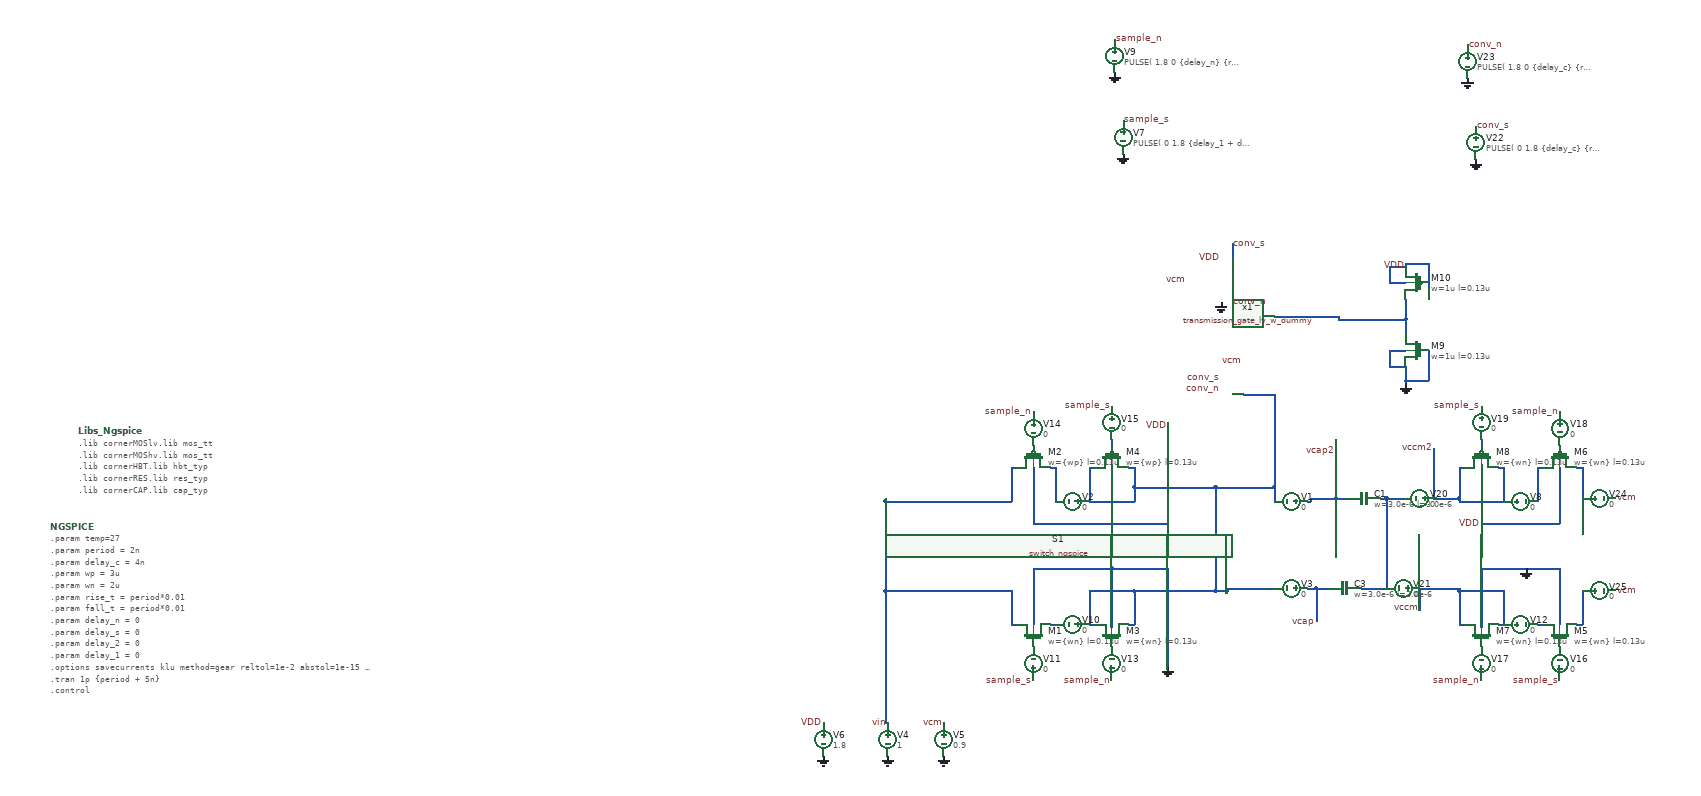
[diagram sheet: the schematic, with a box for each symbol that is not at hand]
v {xschem version=3.4.7 file_version=1.2}
G {}
K {}
V {}
S {}
E {}
N 1585 5 1595 5 {
lab=#net1}
N 1595 5 1595 65 {
lab=#net1}
N 1655 5 1665 5 {
lab=#net2}
N 1655 65 1735 65 {
lab=#net2}
N 1725 5 1735 5 {
lab=#net2}
N 1735 40 1735 65 {
lab=#net2}
N 1515 5 1525 5 {
lab=vin}
N 1515 5 1515 65 {
lab=vin}
N 1515 285 1525 285 {
lab=vin}
N 1515 225 1515 285 {
lab=vin}
N 1655 285 1665 285 {
lab=#net2}
N 1655 225 1735 225 {
lab=#net2}
N 1585 285 1595 285 {
lab=#net3}
N 1555 5 1555 105 {
lab=VDD}
N 1695 105 1795 105 {
lab=VDD}
N 1555 185 1555 285 {
lab=GND}
N 1695 185 1795 185 {
lab=GND}
N 1725 285 1735 285 {lab=#net2}
N 1735 225 1735 285 {lab=#net2}
N 1655 225 1655 285 {lab=#net2}
N 1655 5 1655 65 {lab=#net2}
N 1695 185 1695 290 {lab=GND}
N 1555 185 1695 185 {
lab=GND}
N 1555 105 1695 105 {
lab=VDD}
N 1695 0 1695 105 {lab=VDD}
N 1735 5 1735 40 {
lab=#net2}
N 1795 -75 1795 105 {
lab=VDD}
N 1795 185 1795 365 {
lab=GND}
N 1900 220 1985 220 {lab=#net2}
N 1900 225 1900 230 {lab=#net2}
N 1900 220 1900 225 {lab=#net2}
N 1880 225 1900 225 {
lab=#net2}
N 2060 220 2080 220 {lab=vcap}
N 2060 220 2060 280 {lab=vcap}
N 1695 -45 1695 -35 {lab=#net4}
N 2045 220 2060 220 {lab=vcap}
N 1290 225 1290 460 {lab=vin}
N 1290 65 1515 65 {lab=vin}
N 1290 60 1290 65 {lab=vin}
N 1290 225 1515 225 {lab=vin}
N 1290 65 1290 225 {lab=vin}
N 1290 460 1295 460 {lab=vin}
N 2045 65 2050 65 {lab=vcap2}
N 2050 60 2050 65 {lab=vcap2}
N 2270 60 2315 60 {lab=vccm2}
N 2095 -45 2095 60 {lab=vcap2}
N 2050 60 2095 60 {lab=vcap2}
N 2455 5 2465 5 {
lab=#net5}
N 2455 5 2455 65 {
lab=#net5}
N 2385 5 2395 5 {
lab=vccm2}
N 2315 65 2395 65 {
lab=vccm2}
N 2315 5 2325 5 {
lab=vccm2}
N 2525 5 2535 5 {
lab=#net6}
N 2535 5 2535 65 {
lab=#net6}
N 2525 285 2535 285 {
lab=#net7}
N 2535 225 2535 285 {
lab=#net7}
N 2385 285 2395 285 {
lab=vccm}
N 2315 225 2395 225 {
lab=vccm}
N 2455 285 2465 285 {
lab=#net8}
N 2495 5 2495 105 {
lab=VDD}
N 2495 185 2495 285 {
lab=GND}
N 2315 285 2325 285 {lab=vccm}
N 2315 225 2315 285 {lab=vccm}
N 2395 225 2395 285 {lab=vccm}
N 2395 5 2395 65 {lab=vccm2}
N 2355 185 2355 290 {lab=GND}
N 2355 185 2495 185 {
lab=GND}
N 2355 105 2495 105 {
lab=VDD}
N 2355 0 2355 105 {lab=VDD}
N 2315 60 2315 65 {
lab=vccm2}
N 2355 -45 2355 -35 {lab=#net9}
N 2315 5 2315 60 {
lab=vccm2}
N 2315 220 2315 225 {lab=vccm}
N 2270 -30 2270 60 {lab=vccm2}
N 2245 220 2245 260 {lab=vccm}
N 2245 220 2315 220 {lab=vccm}
N 2095 60 2115 60 {lab=vcap2}
N 2140 220 2185 220 {lab=#net10}
N 2185 60 2215 60 {lab=#net10}
N 1985 40 1985 65 {lab=#net2}
N 1880 40 1880 225 {lab=#net2}
N 1735 40 1880 40 {lab=#net2}
N 1735 225 1880 225 {
lab=#net2}
N 2175 60 2185 60 {lab=#net10}
N 2220 -150 2220 -145 {
lab=GND}
N 2190 -325 2220 -325 {lab=VDD}
N 2190 -355 2190 -325 {lab=VDD}
N 2190 -355 2220 -355 {lab=VDD}
N 2190 -205 2220 -205 {lab=GND}
N 2190 -205 2190 -175 {lab=GND}
N 2190 -175 2220 -175 {lab=GND}
N 2260 -205 2260 -150 {lab=GND}
N 2220 -260 2220 -235 {
lab=#net11}
N 2260 -360 2260 -315 {lab=VDD}
N 2220 -360 2260 -360 {lab=VDD}
N 2220 -360 2220 -355 {lab=VDD}
N 2220 -150 2260 -150 {lab=GND}
N 2220 -175 2220 -150 {
lab=GND}
N 2100 -260 2220 -260 {lab=#net11}
N 2220 -295 2220 -260 {
lab=#net11}
N 2100 -265 2100 -260 {lab=#net11}
N 1985 -265 2100 -265 {lab=#net11}
N 1910 -395 1910 -370 {lab=conv_s}
N 1880 40 1985 40 {lab=#net2}
N 1930 -125 1985 -125 {lab=#net2}
N 1985 -125 1985 40 {lab=#net2}
N 2185 60 2185 220 {lab=#net10}
C {simulator_commands_shown.sym} -150 -60 0 0 {
name=Libs_Ngspice
simulator=ngspice
only_toplevel=false
value="
.lib cornerMOSlv.lib mos_tt
.lib cornerMOShv.lib mos_tt
.lib cornerHBT.lib hbt_typ
.lib cornerRES.lib res_typ
.lib cornerCAP.lib cap_typ
"
      }
C {devices/code_shown.sym} -200 110 0 0 {name=NGSPICE
simulator=ngspice
only_toplevel=false 
value="
.param temp=27
.param period = 2n
.param delay_c = 4n
.param wp = 3u
.param wn = 2u
.param rise_t = period*0.01
.param fall_t = period*0.01
.param delay_n = 0
.param delay_s = 0
.param delay_2 = 0
.param delay_1 = 0
.options savecurrents klu method=gear reltol=1e-2 abstol=1e-15 gmin=1e-10
.tran 1p \{period + 5n\}
.control

run
plot i(v1) i(v3)
plot sample_s sample_n sample_s2+2 sample_n2+2
plot i(v3)-i(v10) i(v10)
plot i(v1)-i(v2) i(v2)
plot i(v14) i(v15) i(v1)-i(v2) i(v2)

plot i(v11) i(v13) i(v3) i(v10)

plot  i(v20) i(v21) 
plot i(v19) i(v18)
plot i(v17) i(v16)
plot i(v24) i(v25)

plot vcap vcap2
plot vccm vccm2
plot vcap-vccm vcap2-vccm2
.endc
"}
C {gnd.sym} 1795 360 0 0 {name=l2 lab=GND}
C {lab_pin.sym} 1555 385 1 1 {name=p1 sig_type=std_logic lab=sample_s}
C {lab_pin.sym} 1695 385 1 1 {name=p6 sig_type=std_logic lab=sample_n}
C {vsource.sym} 2015 65 1 0 {name=V1 value=0 savecurrent=false}
C {vsource.sym} 2015 220 1 0 {name=V3 value=0 savecurrent=false}
C {sg13g2_pr/sg13_lv_nmos.sym} 1555 305 3 0 {name=M1
l=0.13u
w=\{wn\}
ng=1
m=64
model=sg13_lv_nmos
spiceprefix=X
}
C {sg13g2_pr/sg13_lv_pmos.sym} 1555 -15 1 0 {name=M2
l=0.13u
w=\{wp\}
ng=1
m=64
model=sg13_lv_pmos
spiceprefix=X
}
C {lab_pin.sym} 1695 -105 3 1 {name=p25 sig_type=std_logic lab=sample_s}
C {lab_pin.sym} 1555 -95 3 1 {name=p27 sig_type=std_logic lab=sample_n}
C {lab_pin.sym} 1795 -70 0 0 {name=p3 sig_type=std_logic lab=VDD}
C {sg13g2_pr/sg13_lv_nmos.sym} 1695 305 3 0 {name=M3
l=0.13u
w=\{wn\}
ng=1
model=sg13_lv_nmos
spiceprefix=X
m=32}
C {sg13g2_pr/sg13_lv_pmos.sym} 1695 -15 1 0 {name=M4
l=0.13u
w=\{wp\}
ng=1
model=sg13_lv_pmos
spiceprefix=X
m=32}
C {vsource.sym} 1295 490 0 0 {name=V4 value=1 savecurrent=false}
C {lab_pin.sym} 1295 460 0 0 {name=p12 sig_type=std_logic lab=vin}
C {gnd.sym} 1295 520 0 0 {name=l5 lab=GND}
C {vsource.sym} 1395 490 0 0 {name=V5 value=0.9 savecurrent=false}
C {lab_pin.sym} 1395 460 0 0 {name=p13 sig_type=std_logic lab=vcm}
C {gnd.sym} 1395 520 0 0 {name=l6 lab=GND}
C {vsource.sym} 1180 490 0 0 {name=V6 value=1.8 savecurrent=false}
C {lab_pin.sym} 1180 460 0 0 {name=p14 sig_type=std_logic lab=VDD}
C {gnd.sym} 1180 520 0 0 {name=l7 lab=GND}
C {gnd.sym} 1715 -555 0 0 {name=l13 lab=GND}
C {vsource.sym} 1715 -585 0 1 {name=V7 value="PULSE( 0 1.8 \{delay_1 + delay_s\} \{rise_t\} \{fall_t\}  \{period/2\} \{period\} 1)" savecurrent=false}
C {lab_pin.sym} 1715 -615 0 1 {name=p11 sig_type=std_logic lab=sample_s}
C {gnd.sym} 1700 -700 0 0 {name=l4 lab=GND}
C {vsource.sym} 1700 -730 0 0 {name=V9 value="PULSE( 1.8 0 \{delay_n\} \{rise_t\} \{fall_t\} \{period/2\} \{period\} 1)" savecurrent=false}
C {lab_pin.sym} 1700 -760 0 1 {name=p9 sig_type=std_logic lab=sample_n}
C {lab_pin.sym} 2060 280 0 0 {name=p5 sig_type=std_logic lab=vcap}
C {vsource.sym} 1625 65 1 0 {name=V2 value=0 savecurrent=false}
C {vsource.sym} 1625 285 1 0 {name=V10 value=0 savecurrent=false}
C {vsource.sym} 1555 355 2 0 {name=V11 value=0 savecurrent=false}
C {vsource.sym} 1695 355 2 0 {name=V13 value=0 savecurrent=false}
C {vsource.sym} 1555 -65 0 0 {name=V14 value=0 savecurrent=false}
C {vsource.sym} 1695 -75 0 0 {name=V15 value=0 savecurrent=false}
C {lab_pin.sym} 2595 60 0 1 {name=p4 sig_type=std_logic lab=vcm}
C {sg13g2_pr/cap_cmim.sym} 2145 60 3 0 {name=C1
model=cap_cmim
w=3.0e-6
l=3.0e-6
m=64
spiceprefix=X}
C {lab_pin.sym} 2595 225 0 1 {name=p7 sig_type=std_logic lab=vcm}
C {sg13g2_pr/cap_cmim.sym} 2110 220 3 0 {name=C3
model=cap_cmim
w=3.0e-6
l=3.0e-6
m=64
spiceprefix=X}
C {lab_pin.sym} 2095 -25 0 0 {name=p8 sig_type=std_logic lab=vcap2}
C {lab_pin.sym} 2495 385 3 0 {name=p2 sig_type=std_logic lab=sample_s}
C {lab_pin.sym} 2355 385 3 0 {name=p10 sig_type=std_logic lab=sample_n}
C {sg13g2_pr/sg13_hv_nmos.sym} 2495 305 1 1 {name=M5
l=0.13u
w=\{wn\}
ng=1
m=64
model=sg13_lv_nmos
spiceprefix=X
}
C {sg13g2_pr/sg13_hv_pmos.sym} 2495 -15 3 1 {name=M6
l=0.13u
w=\{wn\}
ng=1
m=64
model=sg13_lv_pmos
spiceprefix=X
}
C {lab_pin.sym} 2355 -105 1 0 {name=p15 sig_type=std_logic lab=sample_s}
C {lab_pin.sym} 2495 -95 1 0 {name=p16 sig_type=std_logic lab=sample_n}
C {sg13g2_pr/sg13_hv_nmos.sym} 2355 305 1 1 {name=M7
l=0.13u
w=\{wn\}
ng=1
model=sg13_lv_nmos
spiceprefix=X
m=32}
C {sg13g2_pr/sg13_hv_pmos.sym} 2355 -15 3 1 {name=M8
l=0.13u
w=\{wn\}
ng=1
model=sg13_lv_pmos
spiceprefix=X
m=32}
C {vsource.sym} 2425 65 3 1 {name=V8 value=0 savecurrent=false}
C {vsource.sym} 2425 285 3 1 {name=V12 value=0 savecurrent=false}
C {vsource.sym} 2495 355 2 1 {name=V16 value=0 savecurrent=false}
C {vsource.sym} 2355 355 2 1 {name=V17 value=0 savecurrent=false}
C {vsource.sym} 2495 -65 0 1 {name=V18 value=0 savecurrent=false}
C {vsource.sym} 2355 -75 0 1 {name=V19 value=0 savecurrent=false}
C {gnd.sym} 2435 185 0 0 {name=l1 lab=GND}
C {lab_pin.sym} 2355 105 0 0 {name=p17 sig_type=std_logic lab=VDD}
C {lab_pin.sym} 2270 -30 0 0 {name=p18 sig_type=std_logic lab=vccm2}
C {lab_pin.sym} 2245 255 0 0 {name=p19 sig_type=std_logic lab=vccm}
C {vsource.sym} 2245 60 1 0 {name=V20 value=0 savecurrent=false}
C {vsource.sym} 2215 220 1 0 {name=V21 value=0 savecurrent=false}
C {devices/lab_pin.sym} 2220 -355 1 0 {name=p20 sig_type=std_logic lab=VDD}
C {sg13g2_pr/sg13_lv_nmos.sym} 2240 -205 0 1 {name=M9
l=0.13u
w=1u
ng=1
m=64
model=sg13_lv_nmos
spiceprefix=X
}
C {sg13g2_pr/sg13_lv_pmos.sym} 2240 -325 0 1 {name=M10
l=0.13u
w=1u
ng=1
m=64
model=sg13_lv_pmos
spiceprefix=X
}
C {gnd.sym} 2220 -145 0 0 {name=l3 lab=GND}
C {transmission_gate/transmission_gate_lv_w_dummy.sym} 1910 -330 0 0 {name=x1 W_P=2.0u L_P=0.13u W_N=2.0u L_N=0.13u W_P_D=1.0u L_P_D=0.13u W_N_D=1.0u L_N_D=0.13u n=32}
C {devices/lab_pin.sym} 1890 -370 1 0 {name=p21 sig_type=std_logic lab=VDD}
C {gnd.sym} 1890 -290 0 0 {name=l8 lab=GND}
C {lab_pin.sym} 1830 -330 2 1 {name=p22 sig_type=std_logic lab=vcm}
C {gnd.sym} 2345 -545 0 0 {name=l10 lab=GND}
C {vsource.sym} 2345 -575 0 1 {name=V22 value="PULSE( 0 1.8 \{delay_c\} \{rise_t\} \{fall_t\}  \{period/2\} \{period\} 1)" savecurrent=false}
C {lab_pin.sym} 2345 -605 0 1 {name=p24 sig_type=std_logic lab=conv_s}
C {gnd.sym} 2330 -690 0 0 {name=l11 lab=GND}
C {vsource.sym} 2330 -720 0 0 {name=V23 value="PULSE( 1.8 0 \{delay_c\} \{rise_t\} \{fall_t\} \{period/2\} \{period\} 1)" savecurrent=false}
C {lab_pin.sym} 2330 -750 0 1 {name=p26 sig_type=std_logic lab=conv_n}
C {lab_pin.sym} 1910 -290 0 1 {name=p23 sig_type=std_logic lab=conv_n}
C {lab_pin.sym} 1910 -395 0 1 {name=p28 sig_type=std_logic lab=conv_s}
C {switch_ngspice.sym} 1930 -155 0 0 {name=S1 model=SW1
device_model=".MODEL SW1 SW 
+ VT=0.9 VH=0.01
+ RON=0.01 ROFF=10G "}
C {lab_pin.sym} 1930 -185 2 1 {name=p29 sig_type=std_logic lab=vcm}
C {lab_pin.sym} 1890 -155 0 0 {name=p30 sig_type=std_logic lab=conv_s}
C {lab_pin.sym} 1890 -135 0 0 {name=p31 sig_type=std_logic lab=conv_n}
C {vsource.sym} 2565 60 3 1 {name=V24 value=0 savecurrent=false}
C {vsource.sym} 2565 225 3 1 {name=V25 value=0 savecurrent=false}
